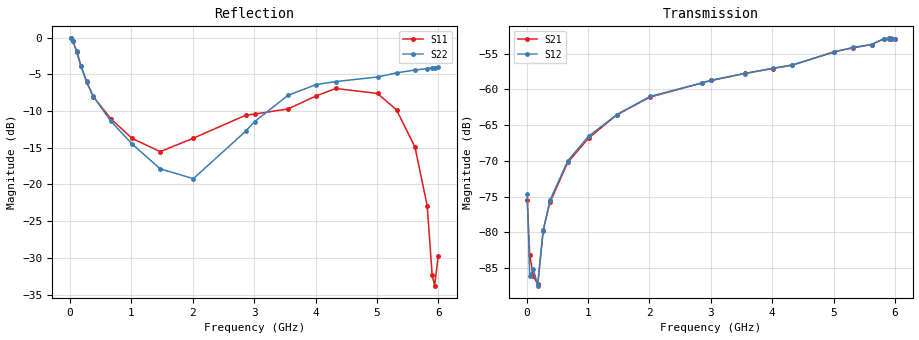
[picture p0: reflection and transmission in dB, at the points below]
!Agilent Technologies,N5230A,MY45001650,A.07.50.48
!Agilent N5230A: A.07.50.48
!Date: Saturday, July 08, 2017 15:52:51
!Correction: S11(Full 2 Port(1,2))
!S21(Full 2 Port(1,2))
!S12(Full 2 Port(1,2))
!S22(Full 2 Port(1,2))
!S2P File: Measurements: S11, S21, S12, S22:
# Hz S  dB  R 50
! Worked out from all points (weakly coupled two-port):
!   600 points, 10 MHz to 6 GHz, reference 50 ohm
!   highest |S21| = -52.87 dB at 5.9 GHz (marker M1); lowest = -87.2 dB at 180 MHz (marker M2)
!   lowest |S11| = -33.8 dB at 5.94 GHz (marker M3), VSWR 1.04, Z = 48.2 - j0.86 ohm
!   |S11| at or under -10 dB: 551 MHz to 3.399 GHz (2.848 GHz wide, 144 % of centre); 3.403 GHz to 3.467 GHz (63.48 MHz wide, 1.85 % of centre); 5.331 GHz to end of sweep
!   |S22| runs from -19.7 to -0.1 dB; largest |S21 - S12| = 0.00013
!   S11 on the Smith chart (normalised r, x): 10 MHz: 2, -19; 110 MHz: 0.49, -1.80; 380 MHz: 0.53, -0.41; 2.86 GHz: 0.60, +0.27; 4.33 GHz: 2.52, +0.50; 6 GHz: 0.96, +0.05
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1e7  -0.12 -6.0  -75.47 -69.3  -74.69 -83.8  -0.11 -5.5
5e7  -0.51 -27.7  -83.16 37.8  -86.12 -179.1  -0.48 -25.4
1.1e8  -1.94 -55.4  -86.13 82.5  -85.14 5.2  -1.88 -50.5
1.8e8  -3.91 -79.6  -87.24 107.8  -87.45 133.8  -3.85 -72.3
2.7e8  -6.03 -102.5  -79.70 96.0  -79.76 102.9  -5.97 -92.0
3.8e8  -8.05 -123.6  -75.81 80.9  -75.51 82.1  -8.02 -108.8
6.7e8  -11.09 -161.0  -70.21 45.0  -69.99 47.6  -11.42 -137.2
1.01e9  -13.72 176.3  -66.81 13.6  -66.55 14.3  -14.47 -154.4
1.47e9  -15.53 166.6  -63.56 -29.5  -63.52 -30.3  -17.87 -170.6
2.01e9  -13.70 172.2  -61.08 -81.3  -60.99 -81.6  -19.21 -171.1
2.86e9  -10.58 136.0  -59.10 -163.1  -59.09 -163.3  -12.77 172.8
3.01e9  -10.41 123.9  -58.76 -176.8  -58.71 -176.6  -11.44 168.7
3.55e9  -9.72 73.1  -57.78 130.7  -57.79 130.7  -7.87 154.4
4.01e9  -7.95 29.9  -57.09 87.6  -57.05 87.8  -6.40 140.7
4.33e9  -6.93 10.1  -56.62 62.9  -56.57 62.8  -5.99 130.7
5.01e9  -7.61 -21.5  -54.73 8.7  -54.80 8.8  -5.37 103.3
5.32e9  -9.84 -35.9  -54.19 -17.4  -54.12 -17.3  -4.81 88.0
5.62e9  -14.91 -53.8  -53.73 -41.1  -53.74 -41.0  -4.42 71.9
5.82e9  -22.92 -72.5  -52.93 -59.0  -52.91 -58.9  -4.23 61.4
5.9e9  -32.30 -99.6  -52.87 -66.7  -52.89 -66.4  -4.09 57.9
5.94e9  -33.78 -154.1  -52.91 -70.4  -52.88 -69.8  -4.08 55.5
6e9  -29.70 131.6  -52.90 -74.9  -53.02 -74.5  -4.01 52.3
